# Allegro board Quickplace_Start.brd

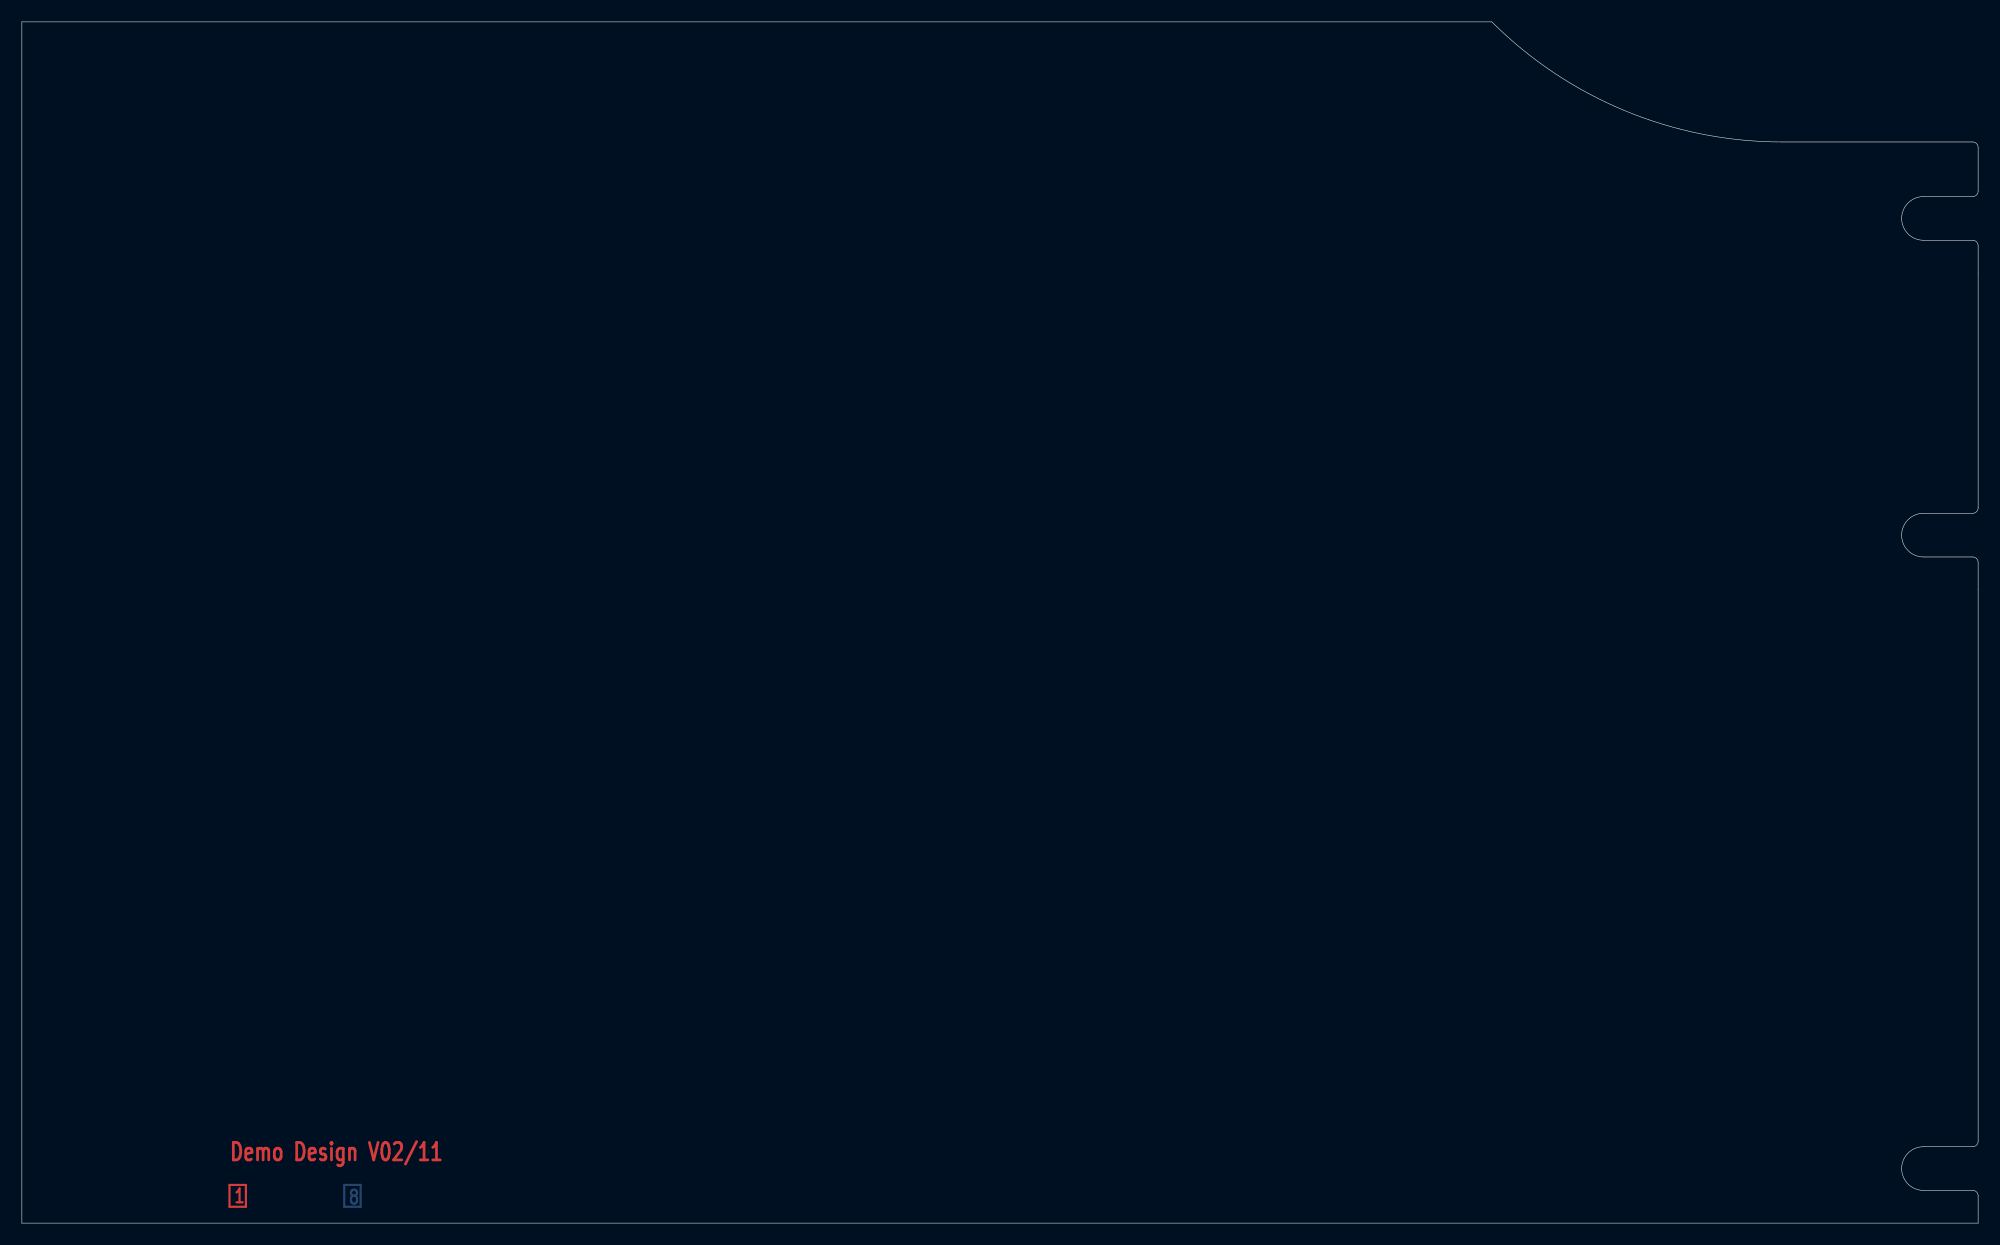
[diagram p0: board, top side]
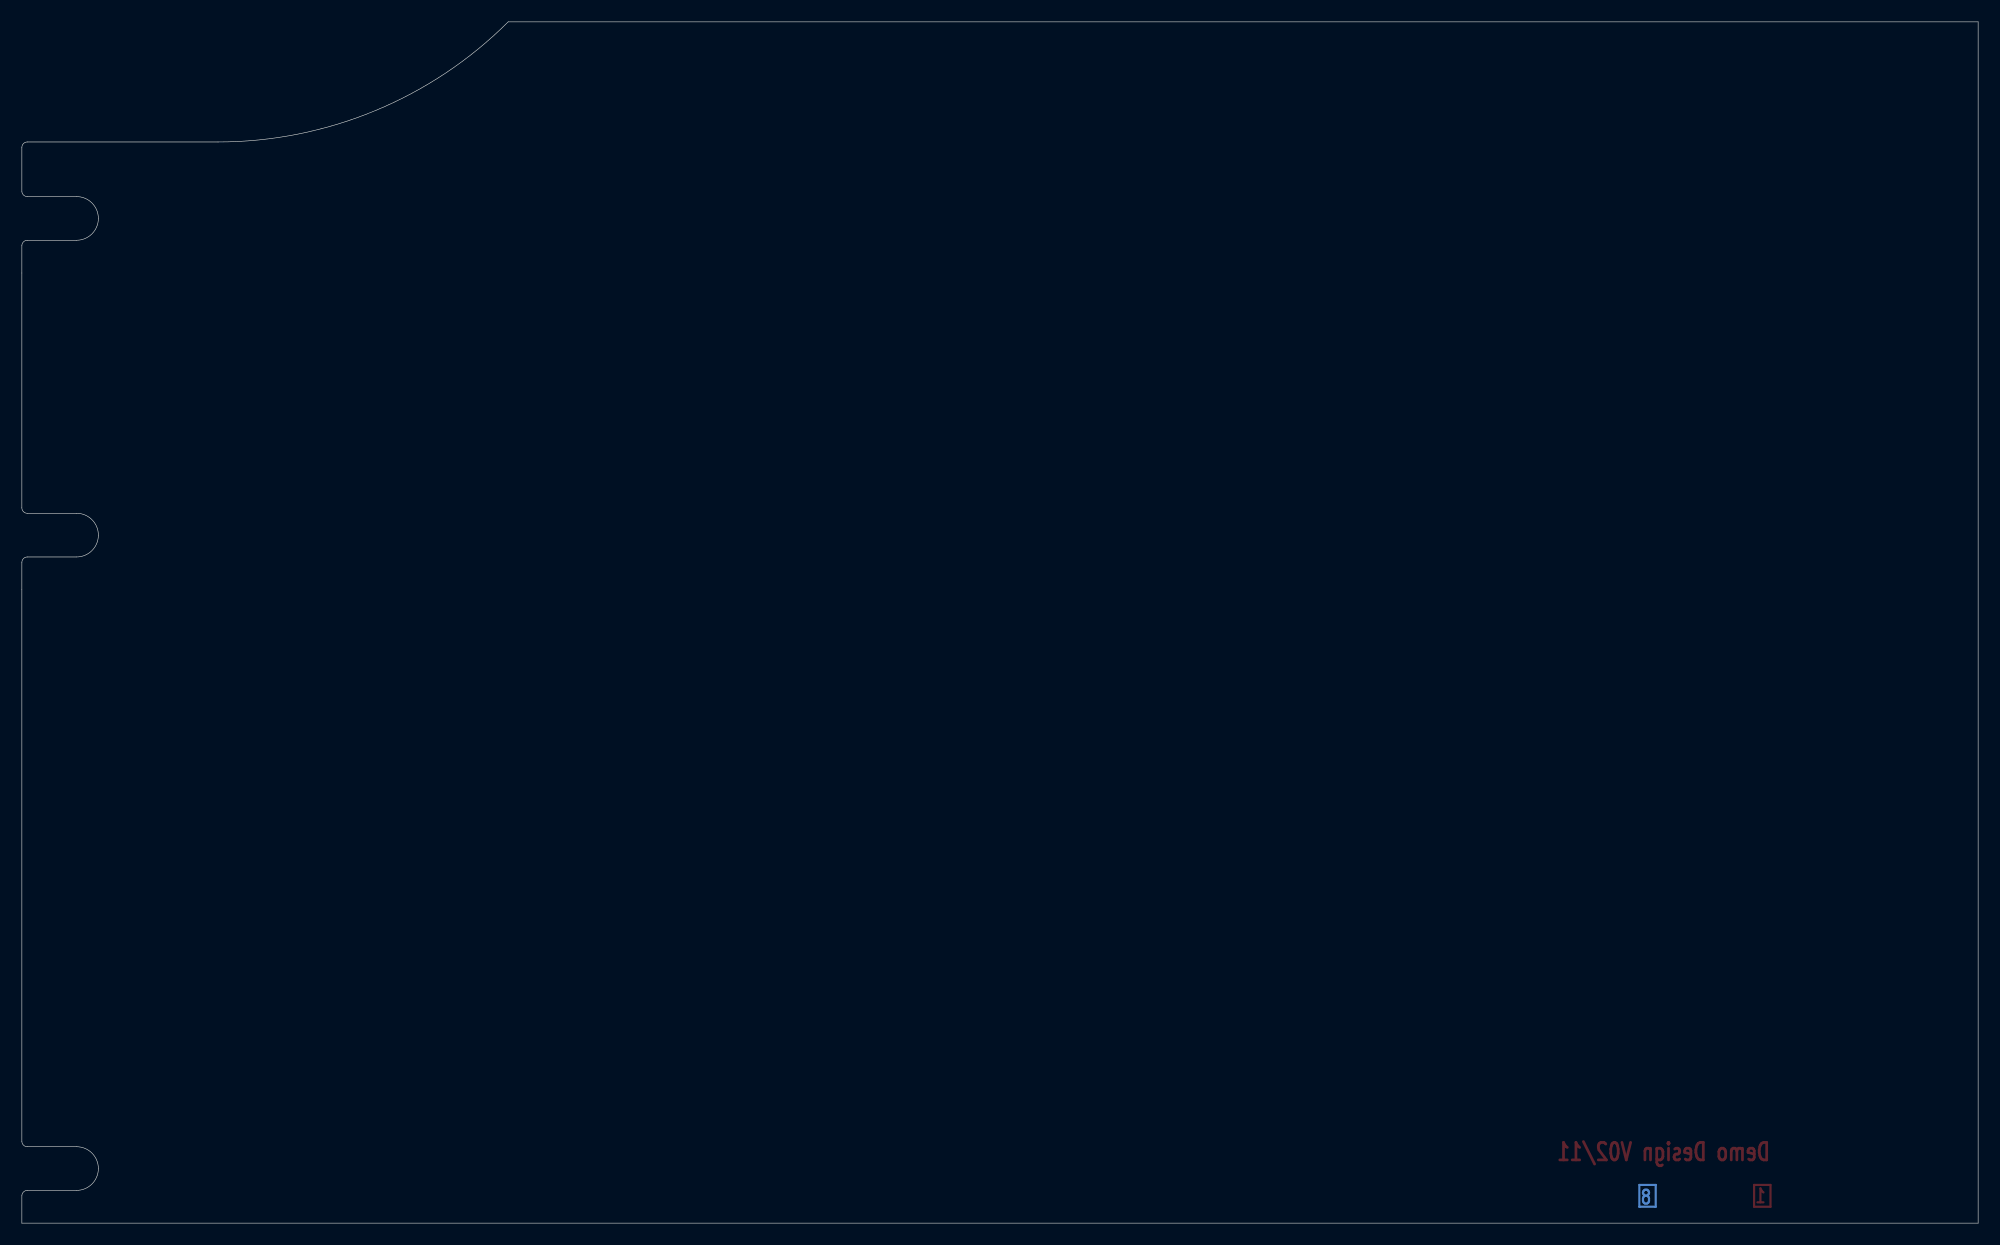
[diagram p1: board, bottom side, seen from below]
Outline 179 x 110 mm; copper layers: TOP, GND1, I1, POW1, GND2, I2, POW2, BOTTOM. Coordinates in mm from the lower left corner of the outline.
Outline path: 0,110 134.5,110 arc(146.68,101.86) 161.06,99 178.5,99 arc(178.85,98.85) 179,98.5 179,94.5 arc(178.85,94.15) 178.5,94 174,94 arc(172.59,93.41) 172,92 arc(172.59,90.59) 174,90 178.5,90 arc(178.85,89.85) 179,89.5 179,65.5 arc(178.85,65.15) 178.5,65 174,65 arc(172.59,64.41) 172,63 arc(172.59,61.59) 174,61 178.5,61 arc(178.85,60.85) 179,60.5 179,7.5 arc(178.85,7.15) 178.5,7 174,7 arc(172.59,6.41) 172,5 arc(172.59,3.59) 174,3 178.5,3 arc(178.85,2.85) 179,2.5 179,0 0,0 0,110

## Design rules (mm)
constraint set DEFAULT: min track width 0.12
net group 220V: nets 220VIN N9903369
net group D+: nets D+ N64620
net group D-: nets D- N64584
net group DDR2.DM0: nets DDR2.DM0 DDR2_M.MDM0
net group DDR2.DM1: nets DDR2.DM1 DDR2_M.MDM1
net group DDR2.DM2: nets DDR2.DM2 DDR2_M.MDM2
net group DDR2.DM3: nets DDR2.DM3 DDR2_M.MDM3
net group DDR2.DQ0: nets DDR2.DQ0 DDR2_M.MDQ0
net group DDR2.DQ1: nets DDR2.DQ1 DDR2_M.MDQ1
net group DDR2.DQ2: nets DDR2.DQ2 DDR2_M.MDQ2
net group DDR2.DQ3: nets DDR2.DQ3 DDR2_M.MDQ3
net group DDR2.DQ4: nets DDR2.DQ4 DDR2_M.MDQ4
net group DDR2.DQ5: nets DDR2.DQ5 DDR2_M.MDQ5
net group DDR2.DQ6: nets DDR2.DQ6 DDR2_M.MDQ6
net group DDR2.DQ7: nets DDR2.DQ7 DDR2_M.MDQ7
net group DDR2.DQ8: nets DDR2.DQ8 DDR2_M.MDQ8
net group DDR2.DQ9: nets DDR2.DQ9 DDR2_M.MDQ9
net group DDR2.DQ10: nets DDR2.DQ10 DDR2_M.MDQ10
net group DDR2.DQ11: nets DDR2.DQ11 DDR2_M.MDQ11
net group DDR2.DQ12: nets DDR2.DQ12 DDR2_M.MDQ12
net group DDR2.DQ13: nets DDR2.DQ13 DDR2_M.MDQ13
net group DDR2.DQ14: nets DDR2.DQ14 DDR2_M.MDQ14
net group DDR2.DQ15: nets DDR2.DQ15 DDR2_M.MDQ15
net group DDR2.DQ16: nets DDR2.DQ16 DDR2_M.MDQ16
net group DDR2.DQ17: nets DDR2.DQ17 DDR2_M.MDQ17
net group DDR2.DQ18: nets DDR2.DQ18 DDR2_M.MDQ18
net group DDR2.DQ19: nets DDR2.DQ19 DDR2_M.MDQ19
net group DDR2.DQ20: nets DDR2.DQ20 DDR2_M.MDQ20
net group DDR2.DQ21: nets DDR2.DQ21 DDR2_M.MDQ21
net group DDR2.DQ22: nets DDR2.DQ22 DDR2_M.MDQ22
net group DDR2.DQ23: nets DDR2.DQ23 DDR2_M.MDQ23
net group DDR2.DQ24: nets DDR2.DQ24 DDR2_M.MDQ24
net group DDR2.DQ25: nets DDR2.DQ25 DDR2_M.MDQ25
net group DDR2.DQ26: nets DDR2.DQ26 DDR2_M.MDQ26
net group DDR2.DQ27: nets DDR2.DQ27 DDR2_M.MDQ27
net group DDR2.DQ28: nets DDR2.DQ28 DDR2_M.MDQ28
net group DDR2.DQ29: nets DDR2.DQ29 DDR2_M.MDQ29
net group DDR2.DQ30: nets DDR2.DQ30 DDR2_M.MDQ30
net group DDR2.DQ31: nets DDR2.DQ31 DDR2_M.MDQ31
net group DDR2.DQS0: nets DDR2.DQS0 DDR2_M.MDQS0
net group DDR2.DQS1: nets DDR2.DQS1 DDR2_M.MDQS1
net group DDR2.DQS2: nets DDR2.DQS2 DDR2_M.MDQS2
net group DDR2.DQS3: nets DDR2.DQS3 DDR2_M.MDQS3
net group DDR2.DQS#0: nets DDR2.DQS#0 DDR2_M.MDQS#0
net group DDR2.DQS#1: nets DDR2.DQS#1 DDR2_M.MDQS#1
net group DDR2.DQS#2: nets DDR2.DQS#2 DDR2_M.MDQS#2
net group DDR2.DQS#3: nets DDR2.DQS#3 DDR2_M.MDQS#3
net group DDR2.RDQS#0: nets DDR2.RDQS#0 DDR2_M.MRDQS#0
net group DDR2.RDQS#1: nets DDR2.RDQS#1 DDR2_M.MRDQS#1
net group DDR2.RDQS#2: nets DDR2.RDQS#2 DDR2_M.MRDQS#2
net group DDR2.RDQS#3: nets DDR2.RDQS#3 DDR2_M.MRDQS#3
net group DDR2[0..71]: nets DDR2.CK1 DDR2.CK#1
net group DDR3.DQ1: nets DDR3.DQ1 DDR3_M.MDQ1
net group DDR3.DQ2: nets DDR3.DQ2 DDR3_M.MDQ2
net group DDR3.DQS0: nets DDR3.DQS0 DDR3_M.MDQS0
net group DDR3.DQS#0: nets DDR3.DQS#0 DDR3_M.MDQS#0
net group L: nets N9927430 N9927434
net group LVDS_CLKN1: nets LVDS_CLKN1 N11185
net group LVDS_CLKP1: nets LVDS_CLKP1 N09783
net group N04579: nets N04579 N05028
net group N06416: nets N06416 N06432
net group N07590: nets N07590 N07606
net group N08030: nets N08030 N08046
net group N14938: nets N04399 N14938
net group N14942: nets N04484 N14942
net group N15446: nets N04241 N15446
net group N15450: nets N04318 N15450
net group PCIE.PERN0: nets N56952 PCIE.PERN0
net group PCIE.PERN1: nets N56956 PCIE.PERN1
net group PCIE.PERN2: nets N56950 PCIE.PERN2
net group PCIE.PERN3: nets N56954 PCIE.PERN3
net group PCIE.PERP0: nets N57097 PCIE.PERP0
net group PCIE.PERP1: nets N57240 PCIE.PERP1
net group PCIE.PERP2: nets N57385 PCIE.PERP2
net group PCIE.PERP3: nets N57532 PCIE.PERP3
net group PCIE.PETN0: nets N58134 PCIE.PETN0
net group PCIE.PETN1: nets N58138 PCIE.PETN1
net group PCIE.PETN2: nets N58142 PCIE.PETN2
net group PCIE.PETN3: nets N58146 PCIE.PETN3
net group PCIE.PETP0: nets N58154 PCIE.PETP0
net group PCIE.PETP1: nets N58162 PCIE.PETP1
net group PCIE.PETP2: nets N58150 PCIE.PETP2
net group PCIE.PETP3: nets N58158 PCIE.PETP3
net group PCIE.REFCLK+: nets N06722 PCIE.REFCLK+
net group PCIE.REFCLK-: nets N06858 PCIE.REFCLK-
net group STDA_SSRX+: nets N64724 STDA_SSRX+
net group STDA_SSRX-: nets N64696 STDA_SSRX-
net group STDA_SSTX+: nets N64864 STDA_SSTX+
net group STDA_SSTX-: nets N64816 STDA_SSTX-
net group AD_DA: nets AD_CS AD_DB0 AD_DB1 AD_DB2 AD_DB3 AD_DB4 AD_DB5 AD_DB6 AD_DB7 AD_DB8 AD_DB9 AD_DB10 AD_DB11 AD_DB12 AD_DB13 AD_FL0 AD_FL1 AD_IRQ2 AD_RD N00752 N00770 N00798 N00829 N00863 N00900 N01007 N01138 N01306 N01356 N01440 N01527 N01617 N01710 N04350 N06404 N07578 N08018
net group DDR2_M.MA0: nets DDR2.A0
net group DDR2_M.MA1: nets DDR2.A1
net group DDR2_M.MA2: nets DDR2.A2
net group DDR2_M.MA3: nets DDR2.A3
net group DDR2_M.MA4: nets DDR2.A4
net group DDR2_M.MA5: nets DDR2.A5
net group DDR2_M.MA6: nets DDR2.A6
net group DDR2_M.MA7: nets DDR2.A7
net group DDR2_M.MA8: nets DDR2.A8
net group DDR2_M.MA9: nets DDR2.A9
net group DDR2_M.MA10: nets DDR2.A10
net group DDR2_M.MA11: nets DDR2.A11
net group DDR2_M.MA12: nets DDR2.A12
net group DDR2_M.MA13: nets DDR2.A13
net group DDR2_M.MBA0: nets DDR2.BA0
net group DDR2_M.MBA1: nets DDR2.BA1
net group DDR2_M.MCAS: nets DDR2.CAS
net group DDR2_M.MCKE0: nets DDR2.CKE0
net group DDR2_M.MODT0: nets DDR2.ODT0
net group DDR2_M.MRAS: nets DDR2.RAS
net group DDR2_M.MS0: nets DDR2.S0
net group DDR2_M.MWE: nets DDR2.WE
net group DDR3.DQ0: nets DDR3.DQ0
net group DDR3.DQ3: nets DDR3.DQ3
net group DDR3.DQ4: nets DDR3.DQ4
net group DDR3.DQ5: nets DDR3.DQ5
net group DDR3.DQ6: nets DDR3.DQ6
net group DDR3.DQ7: nets DDR3.DQ7
net group DDR3.DQ8: nets DDR3.DQ8
net group DDR3.DQ9: nets DDR3.DQ9
net group DDR3.DQ10: nets DDR3.DQ10
net group DDR3.DQ11: nets DDR3.DQ11
net group DDR3.DQ12: nets DDR3.DQ12
net group DDR3.DQ13: nets DDR3.DQ13
net group DDR3.DQ14: nets DDR3.DQ14
net group DDR3.DQ15: nets DDR3.DQ15
net group DDR3.DQS1: nets DDR3.DQS1
net group DDR3.DQS2: nets DDR3.DQS2
net group DDR3.DQS3: nets DDR3.DQS3
net group DDR3.DQS#1: nets DDR3.DQS#1
net group DDR3.DQS#2: nets DDR3.DQS#2
net group DDR3.DQS#3: nets DDR3.DQS#3
net group DDR3[0..54]: nets DDR3.A0 DDR3.A1 DDR3.A2 DDR3.A3 DDR3.A4 DDR3.A5 DDR3.A6 DDR3.A7 DDR3.A8 DDR3.A9 DDR3.A10 DDR3.A11 DDR3.A12 DDR3.A13 DDR3.A14 DDR3.BA0 DDR3.BA1 DDR3.BA2 DDR3.CAS DDR3.CK1 DDR3.CK#1 DDR3.CKE0 DDR3.ODT0 DDR3.RAS DDR3.RESET DDR3.S0 DDR3.WE
net group DDR3_M.MDM0: nets DDR3.DM0
net group DDR3_M.MDM1: nets DDR3.DM1
net group DDR3_M.MDM2: nets DDR3.DM2
net group DDR3_M.MDM3: nets DDR3.DM3
net group DDR3_SINGLE: nets N6521820 N6522732 N6522947 N6523197 N6859922
net group LOGIC: nets N01473 N01729 PGOOD_1.5V PGOOD_1.8V
net group MISC: nets 0.9VREF 0.75VREF 0VIN 1.2V 3.3V FB GATE N00305 N01108 N01139 N01192 N01323 N01619 N03618 N03634 N20586 N20602 N20606 N20610 N20650 N20774 N633172 N633472 N633476 N633480 N633520 N633648 N9903199 N9903225 N9903279 N9903519 N9908752 PE SENSE SHIELD1 SHIELD2 SKIP VCC VINT
net group N: nets N9927466
net group PCI_SINGLE: nets TDIO
net group PCIE[0..23]: nets PCIE.PERST# PCIE.PRSNT#1 PCIE.PRSNT#2 PCIE.SMCLK PCIE.SMDAT PCIE.WAKE#
net group POWER: nets 0.75VTT 1.0V 1.5V 1.8V 2.5V 2.5VREF 5V 12V +15V -15V AGND DGND GND_IN N00359 N00418 N00468 N04407 N04552 N20590 N20594 N20598 N20626 N20798 N20810 N633192 N633212 N633232 N633496 N633672 N633684
net group POWER_IN: nets DRAIN
net group VID: nets VID_D0 VID_D1 VID_D2 VID_D3 VID_D4 VID_FST VID_QCLK VID_SCL

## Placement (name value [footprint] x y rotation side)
NOREF  -  []  0 0 90 top
NOREF#2  -  []  0 0 90 top
NOREF#3  -  []  213.2 115.2 0 top
NOREF#4  -  []  134.5 110 0 top
NOREF#5  -  []  -50.46 -133.7 0 top
NOREF#6  -  []  0 0 0 top
NOREF#7  -  []  15.87 7.79 0 top
NOREF#8  -  []  179 0 90 top
NOREF#9  -  []  0 0 0 top
NOREF#10  -  []  3.11 5.64 0 top
NOREF#11  -  []  0 0 0 top
NOREF#12  -  []  172 5 90 top
NOREF#13  -  []  179 0 90 top
NOREF#14  -  []  179 0 90 top
NOREF#15  -  []  178.88 7.17 90 top
NOREF#16  -  []  0 0 0 top
NOREF#17  -  []  178.5 99 90 top
NOREF#18  -  []  13 5 90 top

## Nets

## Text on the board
BOTTOM: 8
TOP: 1 | Demo Design V02/11
GND1: 2
I1: 3
POW1: 4
GND2: 5
I2: 6
POW2: 7
User.11: FIGURE | SIZE | 0.2 | 0.7 | 1.0 | 1.2 | 1.5 | 1.7 | 2.3 | 2.35 | 3.5 | TOLERANCE | +0.1/-0.1 | +0.0/-0.0 | DRILL CHART: TOP to BOTTOM | ALL UNITS ARE IN MILLIMETERS | PLATED | NON-PLATED | QTY | 1267 | 73 | 44 | 6 | 2 | 19 | 3
User.12: FIGURE | SIZE | 0.2 | TOLERANCE | +0.1/-0.1 | DRILL CHART: I1 to I2 | ALL UNITS ARE IN MILLIMETERS | PLATED | QTY | 35
User.13: FIGURE | SIZE | 0.07 | TOLERANCE | +0.1/-0.1 | DRILL CHART: GND1 to I1 | ALL UNITS ARE IN MILLIMETERS | PLATED | QTY | 63
User.14: FIGURE | SIZE | 0.07 | TOLERANCE | +0.1/-0.1 | DRILL CHART: TOP to GND1 | ALL UNITS ARE IN MILLIMETERS | PLATED | QTY | 63
